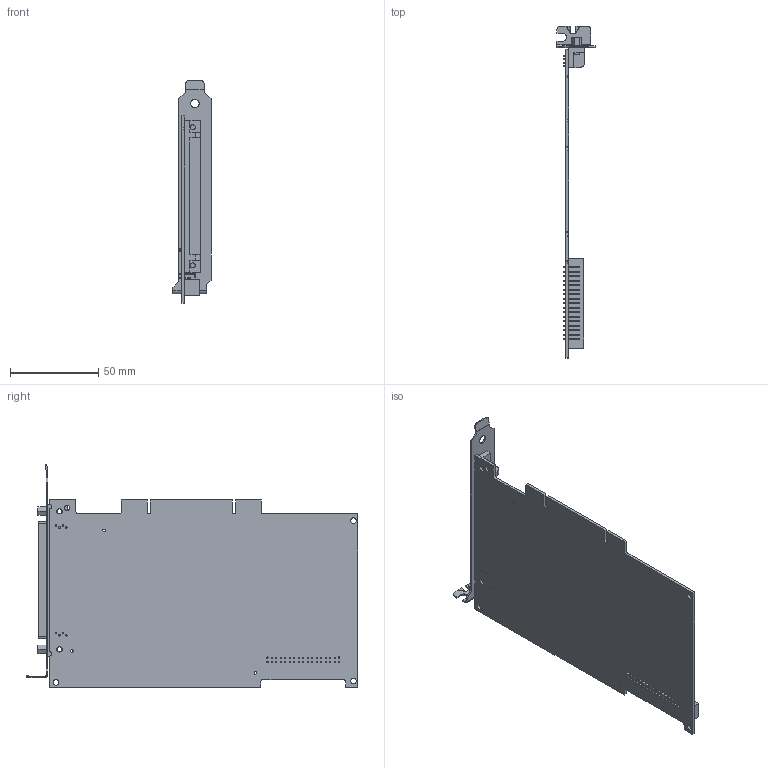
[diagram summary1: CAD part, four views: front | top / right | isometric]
IGES file: header records copied from the file, then geometry measured from it (millimetres).
Start section:  PTC IGES file: cu_pci-100pos_scsi.igs
Global section: file name: cu_pci-100pos_scsi.igs; native system: Creo Parametric by PTC Inc.; preprocessor: 2015380; author: dkendric; organization: Unknown; date: 20160719.162339; units: inch
Bounding box: 21.59 x 187.9 x 126.21 mm (x, y, z)
Surface area: 46002.1 mm2 (no closed solid volume)
Topology: 0 solids, 0 shells, 825 faces, 4490 edges, 4484 vertices
Faces by surface type: bspline 641, revolution 184
